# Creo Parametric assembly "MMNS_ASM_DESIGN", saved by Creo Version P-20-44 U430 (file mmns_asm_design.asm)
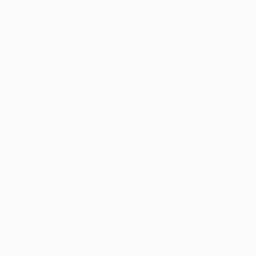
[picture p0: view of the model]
Units: millimeter Newton Second (mmNs); MM, TONNE, SECS

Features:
  1. datum plane "ASM_RIGHT"
  2. datum plane "ASM_TOP"
  3. datum plane "ASM_FRONT"
  4. coordinate system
